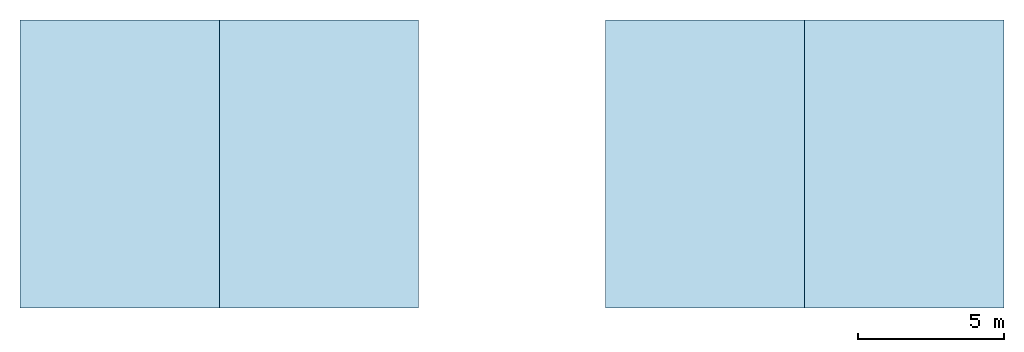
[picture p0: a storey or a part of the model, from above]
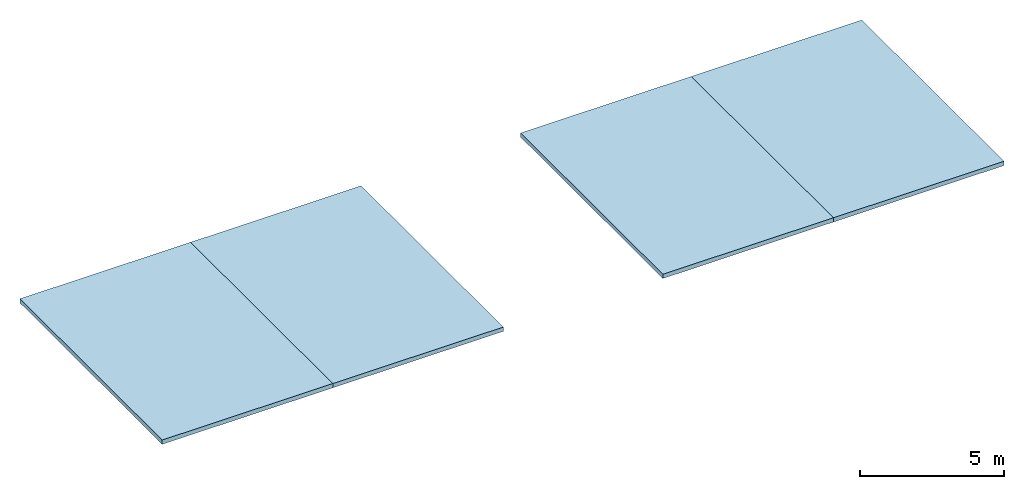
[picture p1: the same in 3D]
Properties of the parts of a building model (IFC2X3)

# File
Description: ViewDefinition [CoordinationView_V2.0], Option [Drawing Scale: 1.000000], Option [Global Unique Identifiers (GUID): Keep existing], Option [Elements to export: Entire project], Option [Partial Structure Display: Entire Model], Option [IFC Domain: All], Option [Structural Function: All Elements], Option [Convert Grid elements: On], Option [Convert IFC Annotations and ARCHICAD 2D elements: Off], Option [Convert 2D symbols of Doors and Windows: Off], Option [Explode Composite and Complex Profile elements into parts: Off], Option [Export geometries that Participates in Collision Detection only: On], Option [Multi-skin complex geometries: Building element parts], Option [Elements in Solid Element Operations: Extruded/revolved], Option [Elements with junctions: Extruded/revolved without junctions], Option [Slabs with slanted edge(s): Extruded], Option [Use legacy geometric methods as in Coordination View 1.0: Off], Option [IFC Site Geometry: As boundary representation (BRep)], Option [IFC Site Location: At Project Origin], Option [Properties To Export: All properties], Option [Space containment: Off], Option [Bounding Box: Off], Option [Geometry to type objects: Off], Option [Element Properties: Off], Option [Element Parameters: Off], Option [IFC Base Quantities: Off], Option [Window Door Lining and Panel Parameters: On], Option [IFC Space boundaries: Off], Option [ARCHICAD Zone Categories as IFC Space classification data: Off]
File name: C:\Users\garcia_d\Desktop\Ochsengasse, Allschwil.ifc
Time: 2017-04-07T10:26:12
Author: Architect
Organization: Building Designer Office
Written by: The EXPRESS Data Manager Version 5.02.0100.09 : 26 Sep 2013
Made in: IFC file generated by GRAPHISOFT ARCHICAD-64 20.0.0 CHE FULL Windows version (IFC2x3 add-on version: 5025 CHE FULL).
Authorization: The authorising person

# IfcSite, Gelände
RefLatitude: 46, 54, 0, 0; RefLongitude: 8, 15, 0, 0; RefElevation: 473 m

# IfcBuildingStorey (4)
In: Gebäude
Name | Elevation (m)
Untergeschoss | -2.63
Erdgeschoss | 0
Dachgeschoss | 2.75
Dachaufsicht | 5.44

# IfcBuildingElementProxy: Beton, Stahlbeton 200 (8)
In: Erdgeschoss
Material: Beton, Stahlbeton
AC_Pset_RenovationAndPhasing - Renovation Status: New
Name
2 x Brüstung A
2 x Brüstung B
2 x Brüstung D
2 x Brüstung C

# IfcSlab: Beton, Stahlbeton 180 (4)
In: Dachaufsicht
Type - PredefinedType: ROOF
Material: Beton, Stahlbeton 0.18 m
Pset_SlabCommon - ThermalTransmittance: 0; LoadBearing: yes; IsExternal: yes
AC_Pset_RenovationAndPhasing - Renovation Status: New
Name
Flachdach A
Flachdach B
Flachdach D
Flachdach C

# IfcSlab: Beton, Stahlbeton 220 (8)
In: Erdgeschoss
Type - PredefinedType: FLOOR
Material: Beton, Stahlbeton 0.22 m
Pset_SlabCommon - ThermalTransmittance: 0; LoadBearing: yes; IsExternal: yes
Zusaetzliche_Element_Eigenschaften_Schweiz - Unter_Terrain: Ja
AC_Pset_RenovationAndPhasing - Renovation Status: New
Name
2 x Bodenplatte A
2 x Bodenplatte B
2 x Bodenplatte D
Decke C
Bodenplatte C

# IfcSlab: Beton, Stahlbeton 240 (4)
In: Dachgeschoss
Type - PredefinedType: FLOOR
Material: Beton, Stahlbeton 0.24 m
Pset_SlabCommon - ThermalTransmittance: 0; LoadBearing: yes; IsExternal: yes
Zusaetzliche_Element_Eigenschaften_Schweiz - Unter_Terrain: Ja
AC_Pset_RenovationAndPhasing - Renovation Status: New
Name
Decke A
Decke B
Decke D
Decke C

# IfcSlab: Beton, Stahlbeton 320 (4)
In: Untergeschoss
Type - PredefinedType: FLOOR
Material: Beton, Stahlbeton 0.32 m
Pset_SlabCommon - ThermalTransmittance: 0; LoadBearing: yes; IsExternal: yes
Zusaetzliche_Element_Eigenschaften_Schweiz - Unter_Terrain: Ja
AC_Pset_RenovationAndPhasing - Renovation Status: New
Name
Fundamentplatte A
Fundamentplatte B
Fundamentplatte D
Fundamentplatte C

# IfcStair (9)
Material: Beton
Name | In | Renovation Status | IsExternal
Treppe A/ (UG-EG) | Untergeschoss | New | no
Treppe B/ (UG-EG) | Untergeschoss | New | no
Treppe D/ (UG-EG) | Untergeschoss | New | no
Treppe C/ (UG-EG) | Untergeschoss | New | no
Treppe A/ (EG-DG) | Erdgeschoss | Existing
2 x Treppe C/ (EG-DG) | Erdgeschoss | Existing
Treppe D/ (EG-DG) | Erdgeschoss | Existing
Treppe-003 | Erdgeschoss | New | yes

# IfcWallStandardCase: Beton, Stahlbeton 150 (8)
In: Untergeschoss
Material: Beton, Stahlbeton 0.15 m
Pset_WallCommon - ThermalTransmittance: 0; LoadBearing: yes; IsExternal: yes
Zusaetzliche_Element_Eigenschaften_Schweiz - Unter_Terrain: Ja; Leichtbau: nicht definiert; beweglich: nicht definiert
AC_Pset_RenovationAndPhasing - Renovation Status: New
Name
2 x Aussenwand A
2 x Aussenwand B
2 x Aussenwand D
2 x Aussenwand C

# IfcWallStandardCase: Beton, Stahlbeton 250 (17)
In: Untergeschoss
Material: Beton, Stahlbeton 0.25 m
Pset_WallCommon - ThermalTransmittance: 0; LoadBearing: yes; IsExternal: yes
Zusaetzliche_Element_Eigenschaften_Schweiz - Unter_Terrain: Ja; Leichtbau: nicht definiert; beweglich: nicht definiert
AC_Pset_RenovationAndPhasing - Renovation Status: New
Name
4 x Aussenwand A
4 x Aussenwand B
5 x Aussenwand D
4 x Aussenwand C

# IfcWallStandardCase: MW, Backstein 120 (45)
Material: MW, Backstein 0.12 m
Pset_WallCommon - ThermalTransmittance: 0; IsExternal: no
Zusaetzliche_Element_Eigenschaften_Schweiz - Leichtbau: nicht definiert; beweglich: nicht definiert
AC_Pset_RenovationAndPhasing - Renovation Status: New
Name | In | Unter_Terrain
4 x Innenwand A | Erdgeschoss | Ja
6 x Innenwand C | Erdgeschoss | Ja
3 x Innenwand D | Erdgeschoss | Ja
8 x Innenwand A | Dachgeschoss | nicht definiert
8 x Innenwand B | Dachgeschoss | nicht definiert
8 x Innenwand D | Dachgeschoss | nicht definiert
8 x Innenwand C | Dachgeschoss | nicht definiert

# IfcWallStandardCase: MW, Backstein 150 (44)
Material: MW, Backstein 0.15 m
Pset_WallCommon - ThermalTransmittance: 0
Zusaetzliche_Element_Eigenschaften_Schweiz - Leichtbau: nicht definiert; beweglich: nicht definiert
AC_Pset_RenovationAndPhasing - Renovation Status: New
Name | In | LoadBearing | IsExternal | Unter_Terrain
3 x Aussenwand A | Erdgeschoss | yes | yes | Ja
Zwischenwand A | Erdgeschoss | yes | yes | Ja
Innenwand A | Erdgeschoss |  | no | Ja
3 x Aussenwand B | Erdgeschoss | yes | yes | Ja
Zwischenwand B | Erdgeschoss | yes | yes | Ja
2 x Innenwand C | Erdgeschoss |  | no | Ja
3 x Aussenwand D | Erdgeschoss | yes | yes | Ja
2 x Wand-004 | Erdgeschoss | yes | yes | Ja
Wand-003 | Erdgeschoss |  | no | Ja
3 x Aussenwand C | Erdgeschoss | yes | yes | Ja
3 x Aussenwand A | Dachgeschoss | yes | yes | nicht definiert
Zwischenwand A | Dachgeschoss | yes | no | nicht definiert
2 x Innenwand A | Dachgeschoss |  | no | nicht definiert
3 x Aussenwand B | Dachgeschoss | yes | yes | nicht definiert
Zwischenwand B | Dachgeschoss | yes | no | nicht definiert
2 x Innenwand B | Dachgeschoss |  | no | nicht definiert
3 x Aussenwand D | Dachgeschoss | yes | yes | nicht definiert
Zwischenwand D | Dachgeschoss | yes | no | nicht definiert
2 x Innenwand D | Dachgeschoss |  | no | nicht definiert
3 x Aussenwand C | Dachgeschoss | yes | yes | nicht definiert
Zwischenwand C | Dachgeschoss | yes | no | nicht definiert
2 x Innenwand C | Dachgeschoss |  | no | nicht definiert

# IfcWallStandardCase: MW, Kalksandstein 120 (16)
In: Untergeschoss
Material: MW, Kalksandstein 0.12 m
Pset_WallCommon - ThermalTransmittance: 0; IsExternal: no
Zusaetzliche_Element_Eigenschaften_Schweiz - Unter_Terrain: Ja; Leichtbau: nicht definiert; beweglich: nicht definiert
AC_Pset_RenovationAndPhasing - Renovation Status: New
Name
4 x Innenwand A
4 x Innenwand B
4 x Innenwand D
4 x Innenwand C

# IfcWallStandardCase: MW, Kalksandstein 150 (16)
In: Untergeschoss
Material: MW, Kalksandstein 0.15 m
Pset_WallCommon - ThermalTransmittance: 0; IsExternal: no
Zusaetzliche_Element_Eigenschaften_Schweiz - Unter_Terrain: Ja; Leichtbau: nicht definiert; beweglich: nicht definiert
AC_Pset_RenovationAndPhasing - Renovation Status: New
Name
3 x Innenwand A
Zwischenwand A | Pset_WallCommon - LoadBearing: no
3 x Innenwand B
Zwischenwand B | Pset_WallCommon - LoadBearing: no
3 x Innenwand D
Zwischenwand D | Pset_WallCommon - LoadBearing: no
3 x Innenwand C
Zwischenwand C | Pset_WallCommon - LoadBearing: no
